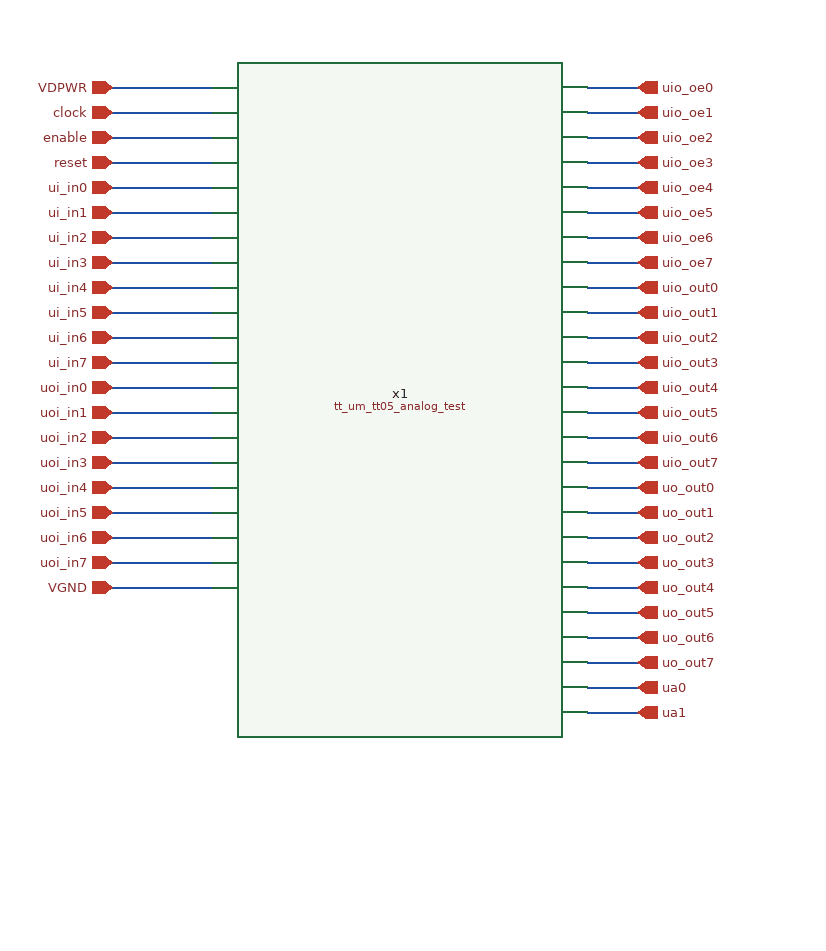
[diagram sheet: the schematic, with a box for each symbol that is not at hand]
v {xschem version=3.4.5 file_version=1.2
}
G {}
K {}
V {}
S {}
E {}
N -240 -300 -160 -300 {
lab=VDPWR}
N -240 -280 -160 -280 {
lab=clock}
N -240 -260 -160 -260 {
lab=enable}
N -240 -240 -160 -240 {
lab=reset}
N -240 -220 -160 -220 {
lab=ui_in0}
N -240 -200 -160 -200 {
lab=ui_in1}
N -240 -180 -160 -180 {
lab=ui_in2}
N -240 -160 -160 -160 {
lab=ui_in3}
N -240 -140 -160 -140 {
lab=ui_in4}
N -240 -120 -160 -120 {
lab=ui_in5}
N -240 -100 -160 -100 {
lab=ui_in6}
N -240 -80 -160 -80 {
lab=ui_in7}
N -240 -60 -160 -60 {
lab=uoi_in0}
N -240 -40 -160 -40 {
lab=uoi_in1}
N -240 -20 -160 -20 {
lab=uoi_in2}
N -240 20 -160 20 {
lab=uoi_in4}
N -240 40 -160 40 {
lab=uoi_in5}
N -240 60 -160 60 {
lab=uoi_in6}
N -240 80 -160 80 {
lab=uoi_in7}
N -240 100 -160 100 {
lab=GND}
N 140 -300 180 -300 {
lab=uio_oe0}
N 140 -280 180 -280 {
lab=uio_oe1}
N 140 -260 180 -260 {
lab=uio_oe2}
N 140 -240 180 -240 {
lab=uio_oe3}
N 140 -220 180 -220 {
lab=uio_oe4}
N 140 -200 180 -200 {
lab=uio_oe5}
N 140 -180 180 -180 {
lab=uio_oe6}
N 140 -160 180 -160 {
lab=uio_oe7}
N 140 -140 180 -140 {
lab=uio_out0}
N 140 -120 180 -120 {
lab=uio_out1}
N 140 -100 180 -100 {
lab=uio_out2}
N 140 -80 180 -80 {
lab=uio_out3}
N 140 -60 180 -60 {
lab=uio_out4}
N 140 -40 180 -40 {
lab=uio_out5}
N 140 -20 180 -20 {
lab=uio_out6}
N 140 0 180 0 {
lab=uio_out7}
N 140 20 180 20 {
lab=uo_out0}
N 140 40 180 40 {
lab=uo_out1}
N 140 60 180 60 {
lab=uo_out2}
N 140 80 180 80 {
lab=uo_out3}
N 140 100 180 100 {
lab=uo_out4}
N 140 180 180 180 {
lab=ua0}
N 140 160 180 160 {
lab=uo_out7}
N 140 140 180 140 {
lab=uo_out6}
N 140 120 180 120 {
lab=uo_out5}
N 140 200 180 200 {
lab=ua1}
N -240 -0 -160 0 {
lab=uoi_in3}
C {tt_um_tt05_analog_test.sym} -10 10 0 0 {name=x1}
C {devices/ipin.sym} -240 -300 0 0 {name=p1 lab=VDPWR}
C {devices/ipin.sym} -240 -280 0 0 {name=p2 lab=clock}
C {devices/ipin.sym} -240 -240 0 0 {name=p3 lab=reset
}
C {devices/ipin.sym} -240 -260 0 0 {name=p4 lab=enable}
C {devices/ipin.sym} -240 -220 0 0 {name=p5 lab=ui_in0

}
C {devices/ipin.sym} -240 -200 0 0 {name=p6 lab=ui_in1

}
C {devices/ipin.sym} -240 -180 0 0 {name=p7 lab=ui_in2

}
C {devices/ipin.sym} -240 -160 0 0 {name=p8 lab=ui_in3

}
C {devices/ipin.sym} -240 -140 0 0 {name=p9 lab=ui_in4

}
C {devices/ipin.sym} -240 -120 0 0 {name=p10 lab=ui_in5

}
C {devices/ipin.sym} -240 -100 0 0 {name=p11 lab=ui_in6

}
C {devices/ipin.sym} -240 -80 0 0 {name=p12 lab=ui_in7

}
C {devices/ipin.sym} -240 -60 0 0 {name=p13 lab=uoi_in0

}
C {devices/ipin.sym} -240 -40 0 0 {name=p14 lab=uoi_in1

}
C {devices/ipin.sym} -240 -20 0 0 {name=p15 lab=uoi_in2

}
C {devices/ipin.sym} -240 0 0 0 {name=p16 lab=uoi_in3

}
C {devices/ipin.sym} -240 20 0 0 {name=p17 lab=uoi_in4

}
C {devices/ipin.sym} -240 40 0 0 {name=p18 lab=uoi_in5

}
C {devices/ipin.sym} -240 60 0 0 {name=p19 lab=uoi_in6

}
C {devices/ipin.sym} -240 80 0 0 {name=p20 lab=uoi_in7

}
C {devices/ipin.sym} -240 100 0 0 {name=p21 lab=VGND

}
C {devices/opin.sym} 180 -300 0 0 {name=p22 lab=uio_oe0}
C {devices/opin.sym} 180 -280 0 0 {name=p23 lab=uio_oe1}
C {devices/opin.sym} 180 -260 0 0 {name=p24 lab=uio_oe2}
C {devices/opin.sym} 180 -240 0 0 {name=p25 lab=uio_oe3}
C {devices/opin.sym} 180 -220 0 0 {name=p26 lab=uio_oe4}
C {devices/opin.sym} 180 -200 0 0 {name=p27 lab=uio_oe5}
C {devices/opin.sym} 180 -180 0 0 {name=p28 lab=uio_oe6}
C {devices/opin.sym} 180 -160 0 0 {name=p29 lab=uio_oe7}
C {devices/opin.sym} 180 -140 0 0 {name=p30 lab=uio_out0}
C {devices/opin.sym} 180 -120 0 0 {name=p31 lab=uio_out1}
C {devices/opin.sym} 180 -100 0 0 {name=p32 lab=uio_out2}
C {devices/opin.sym} 180 -80 0 0 {name=p33 lab=uio_out3}
C {devices/opin.sym} 180 -60 0 0 {name=p34 lab=uio_out4}
C {devices/opin.sym} 180 -40 0 0 {name=p35 lab=uio_out5}
C {devices/opin.sym} 180 -20 0 0 {name=p36 lab=uio_out6}
C {devices/opin.sym} 180 0 0 0 {name=p37 lab=uio_out7}
C {devices/opin.sym} 180 20 0 0 {name=p38 lab=uo_out0}
C {devices/opin.sym} 180 40 0 0 {name=p39 lab=uo_out1}
C {devices/opin.sym} 180 60 0 0 {name=p40 lab=uo_out2}
C {devices/opin.sym} 180 80 0 0 {name=p41 lab=uo_out3}
C {devices/opin.sym} 180 100 0 0 {name=p42 lab=uo_out4}
C {devices/opin.sym} 180 120 0 0 {name=p43 lab=uo_out5}
C {devices/opin.sym} 180 140 0 0 {name=p44 lab=uo_out6}
C {devices/opin.sym} 180 160 0 0 {name=p45 lab=uo_out7}
C {devices/opin.sym} 180 180 0 0 {name=p46 lab=ua0}
C {devices/opin.sym} 180 200 0 0 {name=p47 lab=ua1}
C {devices/noconn.sym} 140 220 0 1 {name=l16}
C {devices/noconn.sym} 140 240 0 1 {name=l1}
C {devices/noconn.sym} 140 260 0 1 {name=l2}
C {devices/noconn.sym} 140 280 0 1 {name=l3}
C {devices/noconn.sym} 140 300 0 1 {name=l4}
C {devices/noconn.sym} 140 320 0 1 {name=l5}
